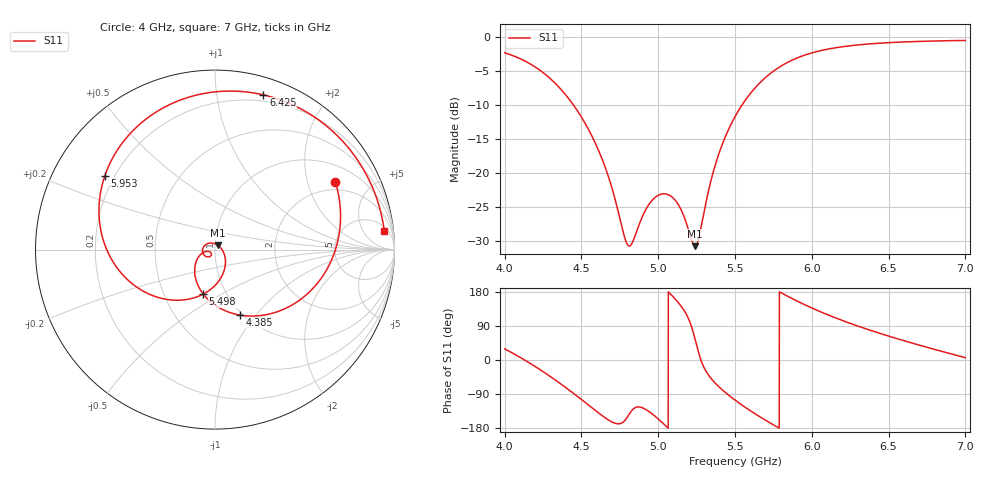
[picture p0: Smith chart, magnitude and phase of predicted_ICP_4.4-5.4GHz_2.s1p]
! ICP-predicted S11, target 4.400-5.400 GHz at -10 dB. Complex ensemble mean (passive and causal);
! its |S11| can differ slightly from the dB-domain mean reported in designs.csv.
!  Air_gap = 2.7mm
!  W_Patch = 12.59mm
!  L_Patch = 20.04mm
!  Sx = 0.36mm
!  Sy = 3.92mm
!  W_Patch1 = 12.74mm
!  WS = 0.57mm
!  Curve_Amp1 = 1.0mm
!  Extra = 6.8mm
# GHz S MA R 50
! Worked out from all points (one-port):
!   3001 points, 4 GHz to 7 GHz, reference 50 ohm
!   lowest |S11| = -30.8 dB at 5.24 GHz (marker M1), VSWR 1.06, Z = 51.6 + j2.44 ohm
!   |S11| at or under -10 dB: 4.449 GHz to 5.545 GHz (1.096 GHz wide, 21.9 % of centre)
!   S11 on the Smith chart (normalised r, x): 4 GHz: 1.62, +3.01; 4.385 GHz: 0.97, -0.84; 5.498 GHz: 0.78, -0.41; 5.953 GHz: 0.16, +0.30; 6.425 GHz: 0.14, +1.35; 7 GHz: 7, +15
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4  0.7698 29.4
4.164  0.6397 -8.3
4.274  0.5232 -37.0
4.375  0.4038 -65.8
4.385  0.3918 -68.8
4.548  0.2076 -119.5
4.66  0.1061 -154.0
4.75  0.0464 -168.1
4.814  0.02892 -141.2
4.976  0.06548 -147.2
5.053  0.06987 -175.2
5.125  0.0599 154.3
5.24  0.02885 54.8
5.265  0.03344 16.2
5.377  0.1199 -63.5
5.498  0.2575 -105.1
5.5  0.26 -105.7
5.587  0.3692 -130.4
5.67  0.4719 -152.0
5.778  0.5926 -177.6
5.875  0.6818 161.5
5.953  0.7392 146.1
6.104  0.8189 119.3
6.25  0.8674 96.7
6.425  0.9034 72.6
6.625  0.9276 47.9
6.814  0.9411 26.3
7  0.9489 6.1
